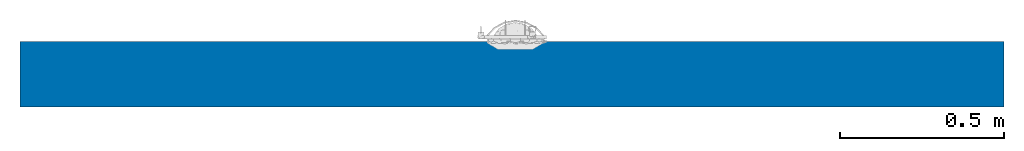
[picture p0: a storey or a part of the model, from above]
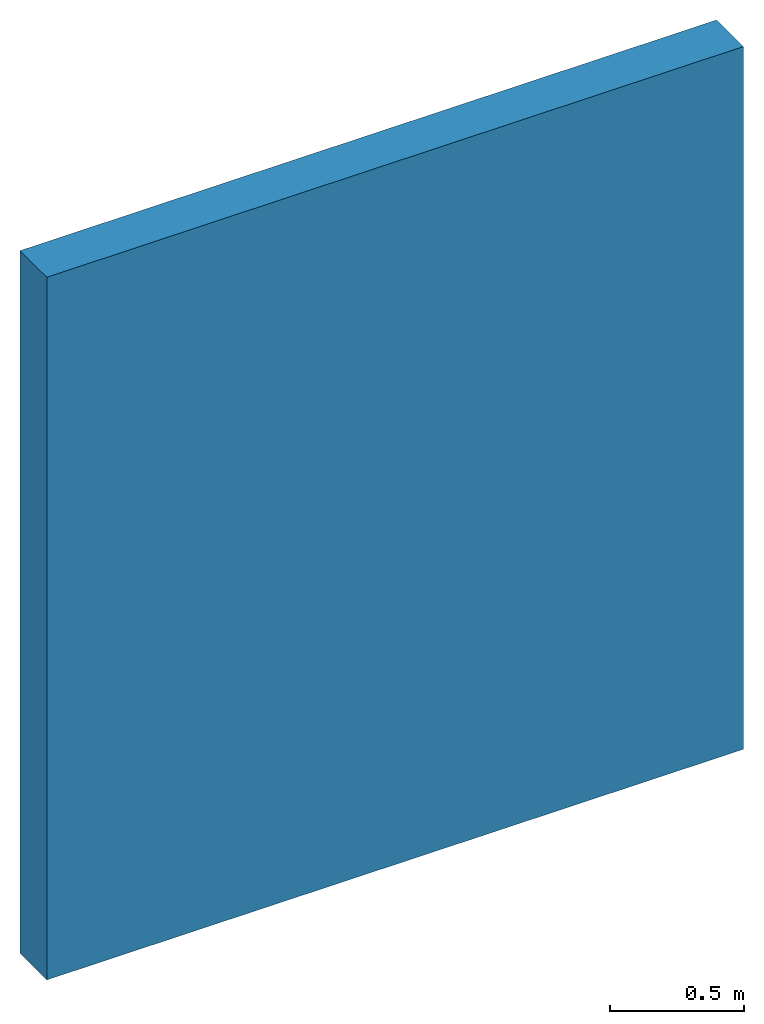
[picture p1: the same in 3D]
Properties of the parts of a building model (IFC2X3)

# File
Description: ViewDefinition [CoordinationView_V2.0], RevitIdentifiers [ContentGUID: 76bb171e-b465-4b72-84d5-03f4dcae93e2, VersionGUID: 31123ab3-2f36-4516-b36c-805b3f107daa, NumberOfSaves: 0], CoordinateReference [CoordinateBase: Shared Coordinates]
File name: Project1.ifc
Time: 2026-02-08T18:39:45+03:30
Written by: ODA SDAI 24.12
Made in: Autodesk Revit 25.4.0.32 (ENU) - IFC 25.4.0.32

# IfcProject, Project Number
LongName: home desing; Phase: Project Status

# IfcSite, Default
RefLatitude: 42, 21, 30, 344238; RefLongitude: -71, -3, -35, -194702; RefElevation: 0 m

# IfcBuilding
Pset_BuildingCommon - NumberOfStoreys: 1

# IfcBuildingStorey: Level:8mm Head (5)
Pset_AirSideSystemInformation - sets with these values: 2
Name | LongName = Name | Elevation (m)
Level 1 | Level 1 | 0
Level 2 | Level 2 | 3.2
Level 3 | Level 3 | 6.4
Level 4 | Level 4 | 9.6
Level 5 | Level 5 | 12.8

# IfcDistributionPort, Port_203629_1
Description: Flow; FlowDirection: SOURCEANDSINK

# IfcFlowTerminal: 10-small-cabin-bulkhead:Variant 1 - Raw Brass, 10-small-cabin-bulkhead:Variant 1 - Raw Brass:203629
In: Level 1
Type - Material: Raw Brass
Type - Pset_ManufacturerTypeInformation - Manufacturer: Lampfix
Pset_DistributionFlowElementCommon - Reference: Variant 1 - Raw Brass; sets with these values: 2

# IfcWallStandardCase: Basic Wall:Wall 20cm2, Basic Wall:Wall 20cm2:202088
In: Level 1
Type - PredefinedType: STANDARD; Material: Default Wall 0.2 m
Pset_QuantityTakeOff - Reference: Wall 20cm2; sets with these values: 2
Pset_WallCommon - Reference: Wall 20cm2; IsExternal: yes; ExtendToStructure: no; LoadBearing: no
